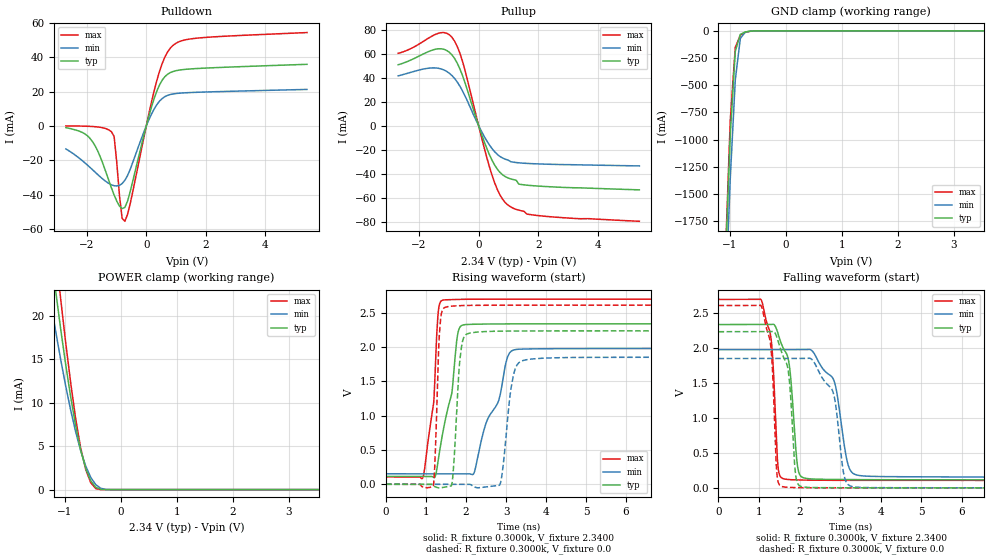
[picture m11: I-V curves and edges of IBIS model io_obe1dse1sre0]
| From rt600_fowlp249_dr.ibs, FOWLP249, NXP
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[Model] io_obe1dse1sre0
|   Model io_obe1dse1sre0
| Library cells for typ/min/max conditions are connected as defined below:
|  pad - External Pad
|  ipp_do - Core Input
|  ipp_obe - Output Buffer Enable
|  REFH3V3 - vdd1v8
|  REFL3V3 - REFL3V3
|  gnde - gnde
|  ipp_dse - vdd
|  ipp_ina235_3v - NC
|  ipp_ina40_3v - NC
|  ipp_ina_mux - NC
|  ipp_ind - NC
|  ipp_ind_1p8v - NC
|  ipp_ind_3v - NC
|  vdd - vdd
|  vdd1v8 - vdd1v8
|  vdda - vdde3v3
|  vdde3v3 - vdde3v3
| All other pins connected to ground
Model_type I/O
Polarity   Non-Inverting
Enable   Active-High
Vinl =   0.7020V
Vinh =   1.6380V
Vmeas =  1.1700V
Cref =   25.0000pF
Rref =   0.5000k
Vref =   0.0V
C_comp   2.0775pF   1.9715pF   2.2888pF
[Temperature Range]   25.0000   0.1250k   -40.0000
[Voltage Range]   2.3400V   1.9800V   2.7000V
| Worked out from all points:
|   slope of the pulldown table from 0 to 0.351 V, typ, clamps not added: 17.4 ohm
|   slope of the pullup table from 0 to 0.351 V, typ, clamps not added: 15 ohm
|   GND clamp passes 1 mA (typ) near -0.56 V on its own axis
|   POWER clamp passes 1 mA (typ) near -0.54 V on its own axis
|   rising waveform, R_fixture 0.3000k, V_fixture 2.3400: 20-80 % time 372ps typ, 611ps min, 218ps max; typ from 0.115 V to 2.34 V
|   rising waveform, R_fixture 0.3000k, V_fixture 0.0: 20-80 % time 131ps typ, 204ps min, 88.5ps max; typ from 0 V to 2.24 V
|   falling waveform, R_fixture 0.3000k, V_fixture 2.3400: 20-80 % time 209ps typ, 378ps min, 147ps max; typ from 2.34 V to 0.115 V
|   falling waveform, R_fixture 0.3000k, V_fixture 0.0: 20-80 % time 190ps typ, 360ps min, 133ps max; typ from 2.24 V to 0 V
[Pulldown]
|Voltage   I(typ)   I(min)   I(max)
-2.7V     -940uA     -13.4mA    60uA
-1.8V     -9.27mA    -25.59mA   -310uA
-1.17V    -36.12mA   -34.32mA   -3.375mA
-1.08V    -40.24mA   -34.85mA   -6.068mA
-810mV    -48.18mA   -33.58mA   -53.87mA
-720mV    -47.53mA   -31.71mA   -55.6mA
-540mV    -38.27mA   -25.32mA   -45.39mA
270mV     16.28mA    10.05mA    20.83mA
540mV     26.85mA    16.1mA     36.66mA
810mV     31.17mA    18.37mA    45.46mA
1.62V     33.44mA    19.6mA     51.09mA
5.4V      35.98mA    21.33mA    54.5mA
[Pullup]
|Voltage   I(typ)   I(min)   I(max)
-2.7V     50.69mA    41.43mA    60.23mA
-1.44V    63.65mA    48.01mA    76.07mA
-1.17V    63.57mA    46.4mA     77.47mA
-900mV    59.06mA    41.81mA    73.72mA
-540mV    41.67mA    28.89mA    53.5mA
90mV      -6.546mA   -4.43mA    -8.951mA
450mV     -28.76mA   -19.1mA    -41.2mA
720mV     -38.99mA   -25.72mA   -57.81mA
990mV     -43.59mA   -28.67mA   -66.23mA
1.35V     -48.7mA    -30.97mA   -70.4mA
1.89V     -50.14mA   -31.77mA   -74.59mA
5.4V      -53.48mA   -33.54mA   -79.66mA
[GND_clamp]
|Voltage   I(typ)   I(min)   I(max)
-2.7V     -30.44A    -30.24A    -31.41A
-1.08V    -2.185A    -2.567A    -2.12A
-990mV    -960.7mA   -1.36A     -827.1mA
-900mV    -189.4mA   -452.2mA   -151.9mA
-810mV    -32.32mA   -70.36mA   -40.6mA
-720mV    -10.56mA   -11.13mA   -13.17mA
-450mV    -34.64uA   -125.9uA   -17.93uA
5.4V      0A         0A         0A
[POWER_clamp]
|Voltage   I(typ)   I(min)   I(max)
-2.7V     98.14mA    78.02mA    112mA
-1.26V    27.63mA    21.78mA    33.04mA
-1.17V    23.01mA    18.34mA    27.46mA
-1.08V    18.61mA    15.06mA    22.08mA
-900mV    10.71mA    9.177mA    12.35mA
-810mV    7.362mA    6.657mA    8.175mA
-720mV    4.554mA    4.475mA    4.783mA
-630mV    2.426mA    2.705mA    2.314mA
-540mV    1.008mA    1.402mA    786.7uA
-450mV    256.5uA    565.2uA    114.6uA
-180mV    74.82nA    2.293uA    9.12nA
5.4V      0A         0A         0A
[Ramp]
| variable   typ   min   max
dV/dt_r  1.0486/0.2562n   0.7644/0.4359n   1.3258/0.1419n
dV/dt_f  0.9298/0.3506n   0.5697/0.6021n   1.2310/0.2113n
R_load = 50.0000
[Rising Waveform]
R_fixture= 0.3000k
V_fixture= 2.3400
V_fixture_min= 1.9800
V_fixture_max= 2.7000
|time   V(typ)   V(min)   V(max)
0s        114.7mV    152.8mV    107mV
912.4ps   114.7mV    152.8mV    92.16mV
1.223ns   109mV      152.8mV    1.604V
1.346ns   514.2mV    152.8mV    2.646V
1.792ns   2.196V     152.8mV    2.696V
1.941ns   2.325V     152.8mV    2.698V
2.202ns   2.334V     170.8mV    2.698V
3.082ns   2.339V     1.912V     2.7V
4.299ns   2.34V      1.978V     2.7V
500ns     2.34V      1.98V      2.7V
[Rising Waveform]
R_fixture= 0.3000k
V_fixture= 0.0
V_fixture_min= 0.0
V_fixture_max= 0.0
|time   V(typ)   V(min)   V(max)
0s        24.57nV    706.2nV    42.75nV
1.177ns   -12.63mV   690nV      -28.79mV
1.359ns   -51.13mV   605.3nV    2.392V
1.634ns   -18.57mV   225.5nV    2.597V
1.849ns   1.842V     276.6nV    2.605V
2.078ns   2.203V     368.7uV    2.609V
2.858ns   2.233V     15.09mV    2.612V
3.317ns   2.235V     1.772V     2.612V
4.795ns   2.237V     1.85V      2.612V
500ns     2.237V     1.853V     2.612V
[Falling Waveform]
R_fixture= 0.3000k
V_fixture= 2.3400
V_fixture_min= 1.9800
V_fixture_max= 2.7000
|time   V(typ)   V(min)   V(max)
0s        2.34V      1.98V      2.7V
1.055ns   2.34V      1.98V      2.692V
1.396ns   2.321V     1.98V      1.164V
1.511ns   2.13V      1.98V      177.2mV
1.748ns   1.756V     1.98V      118.6mV
1.972ns   242.4mV    1.98V      113mV
2.324ns   126.5mV    1.955V     109.8mV
3.272ns   118.3mV    234.3mV    107.5mV
4.573ns   115.8mV    159.3mV    107.1mV
500ns     114.7mV    152.8mV    107mV
[Falling Waveform]
R_fixture= 0.3000k
V_fixture= 0.0
V_fixture_min= 0.0
V_fixture_max= 0.0
|time   V(typ)   V(min)   V(max)
0s        2.237V     1.853V     2.612V
1.062ns   2.237V     1.853V     2.596V
1.294ns   2.237V     1.853V     2.008V
1.4ns     2.214V     1.853V     662.7mV
1.501ns   2.039V     1.853V     44.72mV
2.12ns    10.71mV    1.853V     2.231mV
2.822ns   1.992mV    1.38V      541.6uV
3.155ns   1.294mV    79.42mV    300.9uV
3.877ns   634.1uV    3.165mV    93.74uV
500ns     392.3nV    1.167uV    274nV
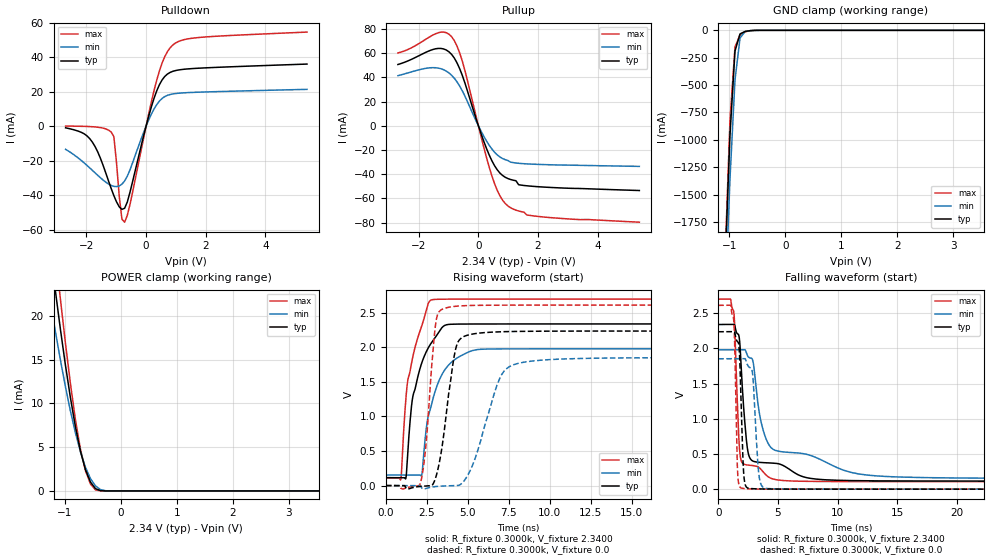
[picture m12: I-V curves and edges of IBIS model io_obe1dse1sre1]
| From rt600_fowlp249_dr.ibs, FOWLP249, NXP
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[Model] io_obe1dse1sre1
|   Model io_obe1dse1sre1
| Library cells for typ/min/max conditions are connected as defined below:
|  pad - External Pad
|  ipp_do - Core Input
|  ipp_obe - Output Buffer Enable
|  REFH3V3 - vdd1v8
|  REFL3V3 - REFL3V3
|  gnde - gnde
|  ipp_dse - vdd
|  ipp_ina235_3v - NC
|  ipp_ina40_3v - NC
|  ipp_ina_mux - NC
|  ipp_ind - NC
|  ipp_ind_1p8v - NC
|  ipp_ind_3v - NC
|  ipp_sre - vdd
|  vdd - vdd
|  vdd1v8 - vdd1v8
|  vdda - vdde3v3
|  vdde3v3 - vdde3v3
| All other pins connected to ground
Model_type I/O
Polarity   Non-Inverting
Enable   Active-High
Vinl =   0.7020V
Vinh =   1.6380V
Vmeas =  1.1700V
Cref =   25.0000pF
Rref =   0.5000k
Vref =   0.0V
C_comp   2.0775pF   1.9715pF   2.2887pF
[Temperature Range]   25.0000   0.1250k   -40.0000
[Voltage Range]   2.3400V   1.9800V   2.7000V
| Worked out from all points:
|   slope of the pulldown table from 0 to 0.351 V, typ, clamps not added: 17.4 ohm
|   slope of the pullup table from 0 to 0.351 V, typ, clamps not added: 15 ohm
|   GND clamp passes 1 mA (typ) near -0.56 V on its own axis
|   POWER clamp passes 1 mA (typ) near -0.54 V on its own axis
|   rising waveform, R_fixture 0.3000k, V_fixture 2.3400: 20-80 % time 1.03ns typ, 1.11ns min, 955ps max; typ from 0.115 V to 2.34 V
|   rising waveform, R_fixture 0.3000k, V_fixture 0.0: 20-80 % time 757ps typ, 1.42ns min, 507ps max; typ from 0 V to 2.24 V
|   falling waveform, R_fixture 0.3000k, V_fixture 2.3400: 20-80 % time 585ps typ, 3.28ns min, 349ps max; typ from 2.34 V to 0.115 V
|   falling waveform, R_fixture 0.3000k, V_fixture 0.0: 20-80 % time 251ps typ, 364ps min, 194ps max; typ from 2.24 V to 0 V
[Pulldown]
|Voltage   I(typ)   I(min)   I(max)
-2.7V     -940uA     -13.4mA    60uA
-1.8V     -9.27mA    -25.59mA   -310uA
-1.17V    -36.12mA   -34.32mA   -3.375mA
-1.08V    -40.24mA   -34.85mA   -6.068mA
-810mV    -48.18mA   -33.58mA   -53.87mA
-720mV    -47.53mA   -31.71mA   -55.6mA
-540mV    -38.27mA   -25.32mA   -45.39mA
270mV     16.28mA    10.05mA    20.83mA
540mV     26.85mA    16.1mA     36.66mA
810mV     31.17mA    18.37mA    45.46mA
1.62V     33.44mA    19.6mA     51.09mA
5.4V      35.98mA    21.33mA    54.5mA
[Pullup]
|Voltage   I(typ)   I(min)   I(max)
-2.7V     50.69mA    41.43mA    60.22mA
-1.44V    63.65mA    48.01mA    76.07mA
-1.17V    63.57mA    46.4mA     77.47mA
-900mV    59.06mA    41.81mA    73.72mA
-540mV    41.67mA    28.88mA    53.5mA
90mV      -6.546mA   -4.43mA    -8.951mA
450mV     -28.76mA   -19.1mA    -41.2mA
720mV     -38.99mA   -25.72mA   -57.81mA
990mV     -43.59mA   -28.67mA   -66.23mA
1.35V     -48.7mA    -30.97mA   -70.4mA
1.89V     -50.14mA   -31.77mA   -74.59mA
5.4V      -53.48mA   -33.54mA   -79.66mA
[GND_clamp]
|Voltage   I(typ)   I(min)   I(max)
-2.7V     -30.44A    -30.24A    -31.41A
-1.08V    -2.185A    -2.567A    -2.12A
-990mV    -960.7mA   -1.36A     -827.1mA
-900mV    -189.4mA   -452.2mA   -151.9mA
-810mV    -32.32mA   -70.36mA   -40.6mA
-720mV    -10.56mA   -11.13mA   -13.17mA
-450mV    -34.64uA   -125.9uA   -17.93uA
5.4V      0A         0A         0A
[POWER_clamp]
|Voltage   I(typ)   I(min)   I(max)
-2.7V     98.14mA    78.02mA    112mA
-1.26V    27.63mA    21.78mA    33.04mA
-1.17V    23.01mA    18.34mA    27.46mA
-1.08V    18.61mA    15.06mA    22.08mA
-900mV    10.71mA    9.177mA    12.35mA
-810mV    7.362mA    6.657mA    8.175mA
-720mV    4.554mA    4.475mA    4.783mA
-630mV    2.426mA    2.705mA    2.314mA
-540mV    1.008mA    1.402mA    786.7uA
-450mV    256.5uA    565.2uA    114.6uA
-180mV    74.82nA    2.293uA    9.12nA
5.4V      0A         0A         0A
[Ramp]
| variable   typ   min   max
dV/dt_r  1.0486/1.6257n   0.7644/3.2081n   1.3258/0.9926n
dV/dt_f  0.9298/7.5501n   0.5697/11.5213n   1.2310/3.9297n
R_load = 50.0000
[Rising Waveform]
R_fixture= 0.3000k
V_fixture= 2.3400
V_fixture_min= 1.9800
V_fixture_max= 2.7000
|time   V(typ)   V(min)   V(max)
0s        114.7mV    152.8mV    107mV
911.3ps   114.7mV    152.8mV    90.37mV
1.217ns   102mV      152.8mV    1.241V
1.318ns   405.7mV    152.8mV    1.492V
1.619ns   1.251V     152.8mV    1.835V
2.173ns   1.763V     143.4mV    2.299V
2.537ns   1.97V      944.7mV    2.602V
3.213ns   2.215V     1.502V     2.697V
7.098ns   2.34V      1.978V     2.7V
500ns     2.34V      1.98V      2.7V
[Rising Waveform]
R_fixture= 0.3000k
V_fixture= 0.0
V_fixture_min= 0.0
V_fixture_max= 0.0
|time   V(typ)   V(min)   V(max)
0s        24.57nV    706.2nV    42.75nV
2.099ns   -12.43mV   -1.361mV   30.36mV
2.419ns   -6.648mV   -44.08mV   519.4mV
2.886ns   24.63mV    -18.92mV   1.978V
3.205ns   263.6mV    -10.85mV   2.501V
4.277ns   1.993V     -757.5uV   2.596V
5.29ns    2.193V     294mV      2.608V
7.257ns   2.228V     1.672V     2.612V
12.72ns   2.237V     1.843V     2.612V
500ns     2.237V     1.853V     2.612V
[Falling Waveform]
R_fixture= 0.3000k
V_fixture= 2.3400
V_fixture_min= 1.9800
V_fixture_max= 2.7000
|time   V(typ)   V(min)   V(max)
0s        2.34V      1.98V      2.7V
1.304ns   2.34V      1.98V      2.516V
1.731ns   2.182V     1.98V      717mV
1.952ns   1.649V     1.98V      393.8mV
2.352ns   713mV      1.942V     345.8mV
2.652ns   442.8mV    1.865V     339.5mV
4.124ns   374.1mV    669.2mV    183.5mV
6.299ns   243.6mV    518.8mV    115.3mV
22.98ns   114.9mV    156mV      107mV
500ns     114.7mV    152.8mV    107mV
[Falling Waveform]
R_fixture= 0.3000k
V_fixture= 0.0
V_fixture_min= 0.0
V_fixture_max= 0.0
|time   V(typ)   V(min)   V(max)
0s        2.237V     1.853V     2.612V
1.289ns   2.237V     1.853V     2.421V
1.587ns   2.102V     1.853V     410.2mV
1.703ns   2.072V     1.853V     90.04mV
2.142ns   206.1mV    1.853V     8.814mV
2.663ns   9.271mV    1.726V     3.206mV
2.925ns   6.285mV    1.557V     2.191mV
3.466ns   3.407mV    140.9mV    1.209mV
4.665ns   1.345mV    5.411mV    515.8uV
500ns     385.7nV    1.165uV    258.8nV
